One B-rep face of a CAD part: STEP entity #825.
In plain terms, the cylindrical face has radius 15 mm (diameter 30 mm), a partial arc.
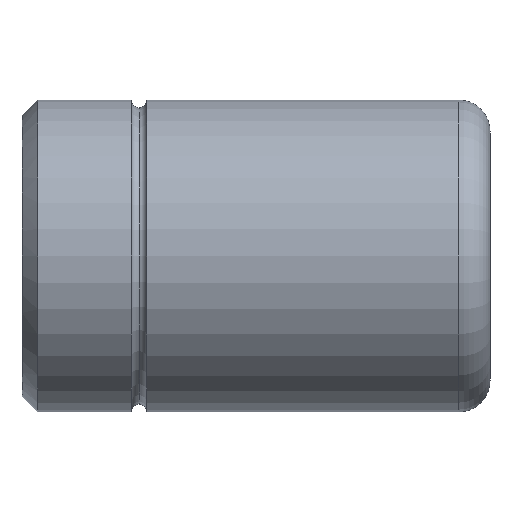
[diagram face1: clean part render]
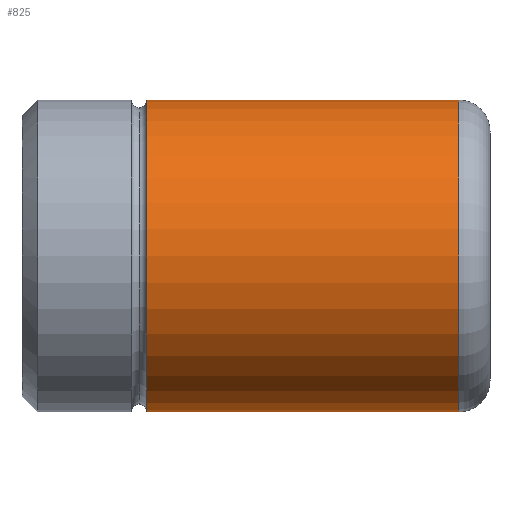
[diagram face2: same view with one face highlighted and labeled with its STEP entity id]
Its self-contained STEP definition (entity closure, numbers rounded to 3 decimals):
#641=CARTESIAN_POINT('Vertex',(12.,0.,15.)) ;
#648=CARTESIAN_POINT('Vertex',(12.,0.,-15.)) ;
#674=CARTESIAN_POINT('Axis2P3D Location',(12.,0.,0.)) ;
#678=CARTESIAN_POINT('Vertex',(12.,-15.,0.)) ;
#681=CARTESIAN_POINT('Axis2P3D Location',(12.,0.,0.)) ;
#765=CARTESIAN_POINT('Line Origine',(45.,0.,15.)) ;
#769=CARTESIAN_POINT('Vertex',(42.,0.,15.)) ;
#783=CARTESIAN_POINT('Vertex',(42.,0.,-15.)) ;
#786=CARTESIAN_POINT('Line Origine',(45.,0.,-15.)) ;
#800=CARTESIAN_POINT('Axis2P3D Location',(45.,0.,0.)) ;
#805=CARTESIAN_POINT('Axis2P3D Location',(42.,0.,0.)) ;
#809=CARTESIAN_POINT('Vertex',(42.,-15.,0.)) ;
#812=CARTESIAN_POINT('Axis2P3D Location',(42.,0.,0.)) ;
#675=DIRECTION('Axis2P3D Direction',(1.,0.,-0.)) ;
#682=DIRECTION('Axis2P3D Direction',(1.,0.,-0.)) ;
#766=DIRECTION('Vector Direction',(-1.,0.,0.)) ;
#787=DIRECTION('Vector Direction',(-1.,0.,0.)) ;
#801=DIRECTION('Axis2P3D Direction',(-1.,-0.,-0.)) ;
#802=DIRECTION('Axis2P3D XDirection',(0.,0.,-1.)) ;
#806=DIRECTION('Axis2P3D Direction',(-1.,-0.,-0.)) ;
#813=DIRECTION('Axis2P3D Direction',(-1.,-0.,-0.)) ;
#676=AXIS2_PLACEMENT_3D('Circle Axis2P3D',#674,#675,$) ;
#683=AXIS2_PLACEMENT_3D('Circle Axis2P3D',#681,#682,$) ;
#803=AXIS2_PLACEMENT_3D('Cylinder Axis2P3D',#800,#801,#802) ;
#807=AXIS2_PLACEMENT_3D('Circle Axis2P3D',#805,#806,$) ;
#814=AXIS2_PLACEMENT_3D('Circle Axis2P3D',#812,#813,$) ;
#818=ORIENTED_EDGE('',*,*,#790,.T.) ;
#819=ORIENTED_EDGE('',*,*,#811,.F.) ;
#820=ORIENTED_EDGE('',*,*,#816,.F.) ;
#821=ORIENTED_EDGE('',*,*,#771,.T.) ;
#822=ORIENTED_EDGE('',*,*,#685,.T.) ;
#823=ORIENTED_EDGE('',*,*,#680,.T.) ;
#767=VECTOR('Line Direction',#766,1.) ;
#788=VECTOR('Line Direction',#787,1.) ;
#825=ADVANCED_FACE('347-19 x 45',(#824),#804,.T.) ;
#677=CIRCLE('generated circle',#676,15.) ;
#684=CIRCLE('generated circle',#683,15.) ;
#808=CIRCLE('generated circle',#807,15.) ;
#815=CIRCLE('generated circle',#814,15.) ;
#804=CYLINDRICAL_SURFACE('generated cylinder',#803,15.) ;
#680=EDGE_CURVE('',#679,#649,#677,.T.) ;
#685=EDGE_CURVE('',#642,#679,#684,.T.) ;
#771=EDGE_CURVE('',#770,#642,#768,.T.) ;
#790=EDGE_CURVE('',#649,#784,#789,.F.) ;
#811=EDGE_CURVE('',#810,#784,#808,.F.) ;
#816=EDGE_CURVE('',#770,#810,#815,.F.) ;
#817=EDGE_LOOP('',(#818,#819,#820,#821,#822,#823)) ;
#824=FACE_OUTER_BOUND('',#817,.T.) ;
#768=LINE('Line',#765,#767) ;
#789=LINE('Line',#786,#788) ;
#642=VERTEX_POINT('',#641) ;
#649=VERTEX_POINT('',#648) ;
#679=VERTEX_POINT('',#678) ;
#770=VERTEX_POINT('',#769) ;
#784=VERTEX_POINT('',#783) ;
#810=VERTEX_POINT('',#809) ;
